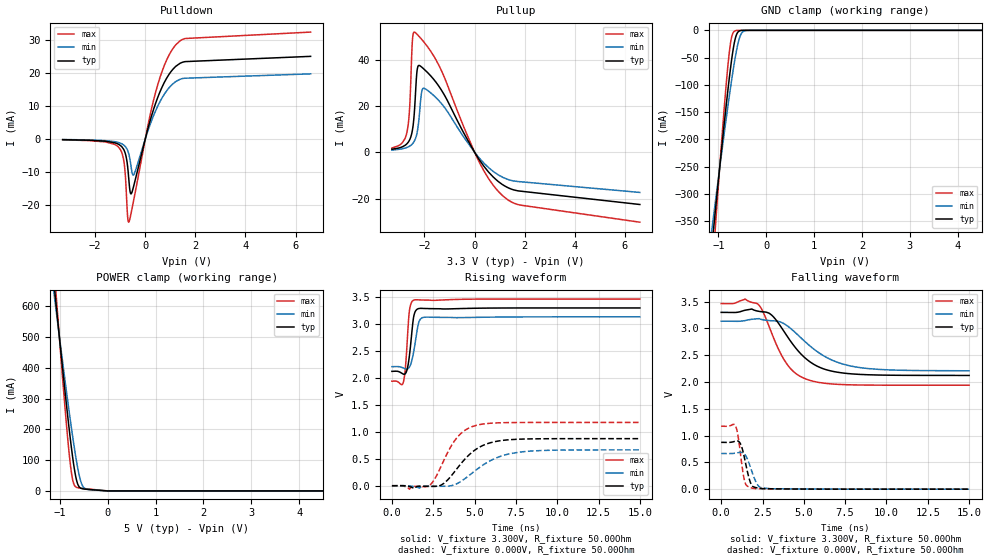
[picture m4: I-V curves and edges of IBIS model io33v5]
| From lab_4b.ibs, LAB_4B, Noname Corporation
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[Model]   io33v5
Model_type   I/O
Vinl = 800.000mV
Vinh = 2.000V
Vmeas = 1.400V
Vref = 1.400V
Cref = 5.000pF
Rref = 100.000Ohm
|   typ   min   max
C_comp   4.550pF   2.600pF   6.500pF
[Voltage Range]   3.300V   3.135V   3.465V
[Power Clamp Reference]   5.000V   4.750V   5.250V
[Temperature Range]   50.0   100.0   0.0
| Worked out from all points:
|   slope of the pulldown table from 0 to 0.495 V, typ, clamps not added: 39.6 ohm
|   slope of the pullup table from 0 to 0.495 V, typ, clamps not added: 64.4 ohm
|   GND clamp passes 1 mA (typ) near -0.56 V on its own axis
|   falling waveform, V_fixture 3.300V, R_fixture 50.00Ohm: 20-80 % time 1.92ns typ, 2.43ns min, 1.47ns max; typ from 3.3 V to 2.12 V
|   rising waveform, V_fixture 3.300V, R_fixture 50.00Ohm: 20-80 % time 247ps typ, 305ps min, 198ps max; typ from 2.12 V to 3.3 V
|   rising waveform, V_fixture 0.000V, R_fixture 50.00Ohm: 20-80 % time 1.64ns typ, 2.03ns min, 1.3ns max; typ from 0 V to 0.874 V
|   falling waveform, V_fixture 0.000V, R_fixture 50.00Ohm: 20-80 % time 392ps typ, 479ps min, 315ps max; typ from 0.874 V to 0 V
[Pulldown]
|   Voltage   I(typ)   I(min)   I(max)
-3.3V     -256.4uA   -208.9uA   -311.8uA
-1.04V    -1.786mA   -1.195mA   -2.784mA
-840mV    -3.589mA   -2.018mA   -7.696mA
-785mV    -4.824mA   -2.467mA   -12.52mA
-710mV    -8.173mA   -3.47mA    -23.22mA
-665mV    -11.73mA   -4.471mA   -25.24mA
-590mV    -16.53mA   -7.344mA   -23.33mA
-465mV    -14.31mA   -10.91mA   -18.6mA
415mV     10.84mA    8.569mA    14.2mA
845mV     18.27mA    14.46mA    23.76mA
1.22V     21.96mA    17.35mA    28.49mA
6.6V      24.96mA    19.66mA    32.31mA
[GND Clamp]
|   Voltage   I(typ)   I(min)   I(max)
-5V       -4.027A    -3.185A    -5.543A
-1.13V    -390.7mA   -361.3mA   -444.8mA
-1.1V     -363.9mA   -340.4mA   -407.5mA
-1.06V    -328.4mA   -312.7mA   -358mA
-885mV    -177.6mA   -194mA     -151.1mA
-785mV    -97.87mA   -129.4mA   -51.4mA
-720mV    -52.41mA   -89.83mA   -11.62mA
-640mV    -13.05mA   -46.25mA   -567uA
-575mV    -1.922mA   -19.09mA   -34.88uA
-520mV    -281.7uA   -5.974mA   -3.374uA
-345mV    -531nA     -33.09uA   -2.101nA
10V       27.06pA    -42.51pA   28.04pA
[Pullup]
|   Voltage   I(typ)   I(min)   I(max)
-3.3V     1.282mA    933.5uA    1.818mA
-2.685V   3.844mA    2.141mA    9.419mA
-2.59V    5.414mA    2.655mA    19.71mA
-2.48V    9.637mA    3.641mA    48.49mA
-2.4V     17.89mA    4.914mA    51.84mA
-2.285V   36.03mA    9.025mA    50.77mA
-2.13V    36.91mA    24.78mA    48.95mA
-2.03V    35.97mA    27.68mA    47.67mA
-1.345V   27.18mA    21.29mA    35.73mA
190mV     -3.263mA   -2.542mA   -4.343mA
1.17V     -14.33mA   -11.03mA   -19.21mA
6.6V      -22.55mA   -17.35mA   -30.18mA
[POWER Clamp]
|   Voltage   I(typ)   I(min)   I(max)
-5V       7.049A     5.735A     9.242A
-1.115V   662.6mA    633mA      714.6mA
-1.085V   615.9mA    595.5mA    652.6mA
-1.06V    577.2mA    564.4mA    601.3mA
-890mV    320.8mA    357mA      266.3mA
-785mV    174.6mA    234.9mA    92.52mA
-715mV    90.33mA    158.6mA    25.97mA
-630mV    23.83mA    77.41mA    10.56mA
-555mV    8.327mA    27.49mA    8.798mA
-490mV    6.13mA     9.246mA    7.697mA
0V        0A         0A         0A
10V       0A         0A         0A
[Ramp]
R_load = 50.00Ohm
|   typ   min   max
dV/dt_r   524.320mV/1.639ns   399.433mV/2.024ns   704.857mV/1.295ns
dV/dt_f   706.191mV/1.919ns   555.207mV/2.425ns   914.908mV/1.471ns
[Falling Waveform]
V_fixture = 3.300V
V_fixture_min = 3.135V
V_fixture_max = 3.465V
R_fixture = 50.00Ohm
|   Time   V(typ)   V(min)   V(max)
0s        3.3V       3.135V     3.465V
1.45ns    3.34V      3.148V     3.549V
2.225ns   3.323V     3.181V     3.453V
2.975ns   3.269V     3.145V     2.977V
3.9ns     2.898V     3.07V      2.371V
4.5ns     2.639V     2.919V     2.163V
5.275ns   2.399V     2.699V     2.04V
6.525ns   2.215V     2.435V     1.968V
8.1ns     2.148V     2.283V     1.946V
15ns      2.123V     2.21V      1.94V
[Rising Waveform]
V_fixture = 3.300V
V_fixture_min = 3.135V
V_fixture_max = 3.465V
R_fixture = 50.00Ohm
|   Time   V(typ)   V(min)   V(max)
0s        2.123V     2.21V      1.94V
700ps     2.071V     2.184V     1.931V
825ps     2.086V     2.169V     2.225V
950ps     2.198V     2.169V     2.808V
1.05ns    2.394V     2.198V     3.227V
1.15ns    2.675V     2.268V     3.379V
1.325ns   3.151V     2.502V     3.446V
1.625ns   3.289V     3.033V     3.45V
1.925ns   3.291V     3.126V     3.447V
15ns      3.3V       3.135V     3.465V
[Rising Waveform]
V_fixture = 0.000V
V_fixture_min = 0.000V
V_fixture_max = 0.000V
R_fixture = 50.00Ohm
|   Time   V(typ)   V(min)   V(max)
0s        210.3nV    222.8nV    217.9nV
1.05ns    -15.36mV   -3.806mV   -63.71mV
2.275ns   -12.4mV    -6.124mV   6.545mV
3.025ns   20.3mV     -9.96mV    394.3mV
3.875ns   293.5mV    30.42mV    868.7mV
4.425ns   497.6mV    133.5mV    1.03V
5.125ns   683.8mV    299.9mV    1.123V
6.3ns     822.7mV    514.8mV    1.166V
7.65ns    863.5mV    620.7mV    1.174V
15ns      873.9mV    665.7mV    1.175V
[Falling Waveform]
V_fixture = 0.000V
V_fixture_min = 0.000V
V_fixture_max = 0.000V
R_fixture = 50.00Ohm
|   Time   V(typ)   V(min)   V(max)
0s        873.9mV    665.7mV    1.175V
875ps     897.8mV    673mV      1.175V
1ns       899.8mV    680mV      1.028V
1.175ns   841.3mV    687.3mV    638.5mV
1.425ns   560.1mV    648.5mV    143.9mV
1.675ns   217.1mV    493.7mV    40.83mV
1.85ns    71.8mV     336.7mV    21.34mV
2.275ns   18.49mV    52.78mV    10.99mV
2.9ns     8.506mV    11.35mV    5.477mV
15ns      210.3nV    222.8nV    217.9nV
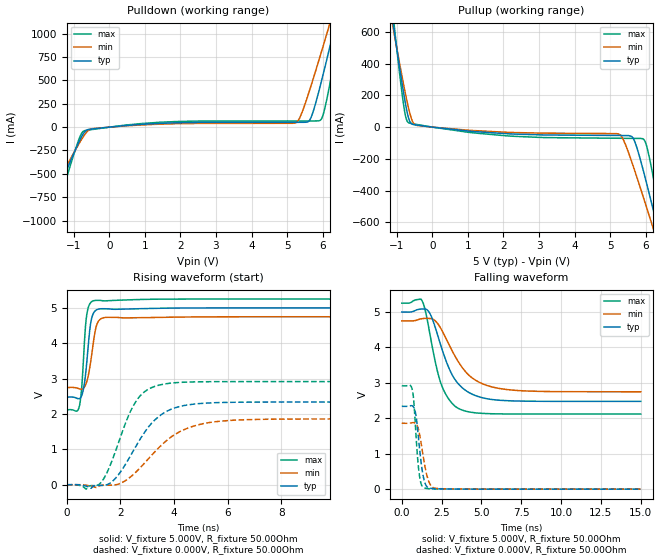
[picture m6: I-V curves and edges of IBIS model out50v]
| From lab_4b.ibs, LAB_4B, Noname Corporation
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[Model]   out50v
Model_type   Output
Vmeas = 1.400V
Vref = 1.400V
Cref = 5.000pF
Rref = 100.000Ohm
|   typ   min   max
C_comp   4.550pF   2.600pF   6.500pF
[Voltage Range]   5.000V   4.750V   5.250V
[Temperature Range]   50.0   100.0   0.0
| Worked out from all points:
|   slope of the pulldown table from 0 to 0.75 V, typ, clamps not added: 29.6 ohm
|   slope of the pullup table from 0 to 0.75 V, typ, clamps not added: 40.8 ohm
|   falling waveform, V_fixture 5.000V, R_fixture 50.00Ohm: 20-80 % time 1.38ns typ, 1.72ns min, 1.02ns max; typ from 5 V to 2.48 V
|   rising waveform, V_fixture 5.000V, R_fixture 50.00Ohm: 20-80 % time 198ps typ, 242ps min, 160ps max; typ from 2.48 V to 5 V
|   rising waveform, V_fixture 0.000V, R_fixture 50.00Ohm: 20-80 % time 1.25ns typ, 1.59ns min, 926ps max; typ from 0 V to 2.34 V
|   falling waveform, V_fixture 0.000V, R_fixture 50.00Ohm: 20-80 % time 355ps typ, 444ps min, 276ps max; typ from 2.34 V to 0 V
[Pulldown]
|   Voltage   I(typ)   I(min)   I(max)
-5V       -4.027A    -3.186A    -5.543A
-2.02V    -1.212A    -998.9mA   -1.596A
-1.595V   -816.4mA   -692.1mA   -1.041A
-870mV    -169.3mA   -186.6mA   -143.1mA
-605mV    -26.32mA   -39.23mA   -31.47mA
5.255V    51.67mA    48.79mA    66.3mA
5.675V    102.2mA    442.2mA    66.49mA
5.985V    517.2mA    828.1mA    99.84mA
6.205V    859.5mA    1.109A     460.6mA
6.325V    1.05A      1.264A     703.1mA
6.525V    1.372A     1.523A     1.123A
10V       7.106A     6.113A     8.761A
[Pullup]
|   Voltage   I(typ)   I(min)   I(max)
-5V       7.053A     5.738A     9.247A
-1.14V    706.4mA    668mA      773.1mA
-1.04V    551.2mA    543.3mA    567.1mA
-780mV    174mA      233.3mA    96.12mA
-665mV    52.44mA    113.3mA    27.17mA
-435mV    12.72mA    10.87mA    16.65mA
5.225V    -52.62mA   -42.21mA   -70.19mA
5.635V    -64.76mA   -235mA     -70.95mA
5.915V    -256.3mA   -427mA     -73.05mA
6.21V     -516.7mA   -636.2mA   -309.2mA
6.53V     -809.9mA   -866.6mA   -706.9mA
10V       -4.086A    -3.416A    -5.289A
[Ramp]
R_load = 50.00Ohm
|   typ   min   max
dV/dt_r   1.403V/1.244ns   1.116V/1.586ns   1.750V/924.101ps
dV/dt_f   1.513V/1.382ns   1.201V/1.723ns   1.878V/1.016ns
[Falling Waveform]
V_fixture = 5.000V
V_fixture_min = 4.750V
V_fixture_max = 5.250V
R_fixture = 50.00Ohm
|   Time   V(typ)   V(min)   V(max)
0s        5V         4.75V      5.25V
1.275ns   5.086V     4.812V     5.317V
1.5ns     5.086V     4.82V      4.998V
1.775ns   4.951V     4.817V     4.359V
2.45ns    4.059V     4.538V     2.998V
3.075ns   3.305V     3.982V     2.467V
3.65ns    2.925V     3.527V     2.259V
4.65ns    2.637V     3.07V      2.154V
6.225ns   2.507V     2.835V     2.124V
15ns      2.478V     2.748V     2.121V
[Rising Waveform]
V_fixture = 5.000V
V_fixture_min = 4.750V
V_fixture_max = 5.250V
R_fixture = 50.00Ohm
|   Time   V(typ)   V(min)   V(max)
0s        2.478V     2.748V     2.121V
475ps     2.437V     2.711V     2.239V
550ps     2.51V      2.703V     2.683V
650ps     2.826V     2.755V     3.919V
725ps     3.3V       2.872V     4.693V
875ps     4.487V     3.396V     5.135V
1ns       4.857V     4.066V     5.203V
1.175ns   4.965V     4.617V     5.214V
1.5ns     4.974V     4.733V     5.202V
15ns      5V         4.75V      5.25V
[Rising Waveform]
V_fixture = 0.000V
V_fixture_min = 0.000V
V_fixture_max = 0.000V
R_fixture = 50.00Ohm
|   Time   V(typ)   V(min)   V(max)
0s        27.12nV    271.5nV    5.17nV
725ps     -40.2mV    -14.6mV    -125.2mV
1.275ns   -18.53mV   -18.42mV   62.91mV
1.825ns   190.8mV    -905.1uV   966mV
2.525ns   1.018V     320.3mV    2.29V
2.9ns     1.481V     613.8mV    2.63V
3.425ns   1.925V     1.042V     2.814V
4.35ns    2.235V     1.55V      2.898V
5.675ns   2.323V     1.793V     2.915V
15ns      2.339V     1.861V     2.916V
[Falling Waveform]
V_fixture = 0.000V
V_fixture_min = 0.000V
V_fixture_max = 0.000V
R_fixture = 50.00Ohm
|   Time   V(typ)   V(min)   V(max)
0s        2.339V     1.861V     2.916V
650ps     2.353V     1.875V     2.828V
750ps     2.311V     1.878V     2.507V
875ps     2.123V     1.854V     1.661V
1.075ns   1.328V     1.643V     507.4mV
1.225ns   717.3mV    1.267V     137mV
1.425ns   219.2mV    717.8mV    36.63mV
1.75ns    32.62mV    160.5mV    12.68mV
2.2ns     11.18mV    21.94mV    6.639mV
15ns      27.12nV    271.5nV    5.17nV
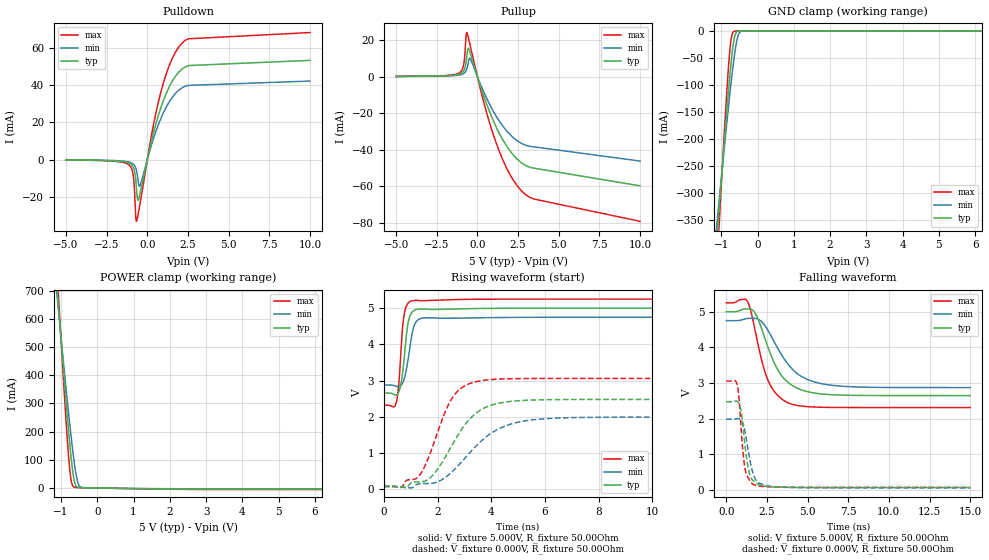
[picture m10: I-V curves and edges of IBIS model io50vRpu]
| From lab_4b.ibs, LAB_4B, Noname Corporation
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[Model]   io50vRpu
Model_type   I/O
Vinl = 800.000mV
Vinh = 2.000V
Vmeas = 1.400V
Vref = 1.400V
Cref = 5.000pF
Rref = 100.000Ohm
|   typ   min   max
C_comp   4.550pF   2.600pF   6.500pF
[Voltage Range]   5.000V   4.750V   5.250V
[Temperature Range]   50.0   100.0   0.0
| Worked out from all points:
|   slope of the pulldown table from 0 to 0.75 V, typ, clamps not added: 29.2 ohm
|   slope of the pullup table from 0 to 0.75 V, typ, clamps not added: 39 ohm
|   GND clamp passes 1 mA (typ) near -0.55 V on its own axis
|   POWER clamp passes 1 mA (typ) near -0.40 V on its own axis
|   falling waveform, V_fixture 5.000V, R_fixture 50.00Ohm: 20-80 % time 1.4ns typ, 1.73ns min, 1.07ns max; typ from 5 V to 2.65 V
|   rising waveform, V_fixture 5.000V, R_fixture 50.00Ohm: 20-80 % time 207ps typ, 250ps min, 169ps max; typ from 2.65 V to 5 V
|   rising waveform, V_fixture 0.000V, R_fixture 50.00Ohm: 20-80 % time 1.28ns typ, 1.63ns min, 951ps max; typ from 0.071 V to 2.48 V
|   falling waveform, V_fixture 0.000V, R_fixture 50.00Ohm: 20-80 % time 403ps typ, 492ps min, 326ps max; typ from 2.48 V to 0.071 V
[Pulldown]
|   Voltage   I(typ)   I(min)   I(max)
-5V       -207.1uA   -171.2uA   -248.8uA
-1.13V    -1.927mA   -1.335mA   -2.852mA
-860mV    -4.389mA   -2.516mA   -9.028mA
-710mV    -11.07mA   -4.645mA   -31mA
-670mV    -15.23mA   -5.818mA   -33.25mA
-575mV    -21.91mA   -10.83mA   -29.94mA
-445mV    -18.01mA   -13.98mA   -23.51mA
265mV     10.33mA    8.149mA    13.57mA
790mV     26.82mA    21.25mA    34.93mA
1.37V     39.56mA    31.41mA    51.13mA
2.085V    48.39mA    38.37mA    62.25mA
10V       53.44mA    42.3mA     68.42mA
[GND Clamp]
|   Voltage   I(typ)   I(min)   I(max)
-5V       -4.027A    -3.186A    -5.543A
-1.13V    -390.8mA   -361.4mA   -445mA
-1.1V     -364mA     -340.5mA   -407.6mA
-1.06V    -328.5mA   -312.8mA   -358.2mA
-885mV    -177.7mA   -194.1mA   -151.3mA
-785mV    -97.96mA   -129.5mA   -51.52mA
-720mV    -52.49mA   -89.9mA    -11.73mA
-640mV    -13.13mA   -46.31mA   -666uA
-575mV    -1.992mA   -19.15mA   -123.8uA
-520mV    -345.2uA   -6.025mA   -83.8uA
-345mV    -42.67uA   -67.14uA   -53.34uA
10V       0A         0A         0A
[Pullup]
|   Voltage   I(typ)   I(min)   I(max)
-5V       149.8uA    122.3uA    183uA
-1.115V   1.394mA    953.8uA    2.1mA
-845mV    3.186mA    1.803mA    6.687mA
-660mV    10.77mA    4.081mA    24.18mA
-570mV    15.65mA    7.386mA    21.72mA
-440mV    12.84mA    9.88mA     16.84mA
340mV     -9.372mA   -7.373mA   -12.34mA
1.035V    -25.27mA   -19.83mA   -33.28mA
1.84V     -38.53mA   -30.1mA    -50.84mA
2.665V    -46.8mA    -36.26mA   -62.03mA
3.52V     -50.13mA   -38.44mA   -67.04mA
10V       -59.71mA   -46.16mA   -79.14mA
[POWER Clamp]
|   Voltage   I(typ)   I(min)   I(max)
-5V       7.64A      6.217A     10.02A
-1.11V    713.1mA    682mA      767.9mA
-1.08V    662.5mA    641.3mA    700.7mA
-1.055V   620.5mA    607.6mA    645mA
-885mV    342.6mA    382.8mA    281.8mA
-780mV    184mA      250.5mA    92.53mA
-715mV    98.29mA    173.5mA    22.03mA
-635mV    24.95mA    88.98mA    2.939mA
-570mV    4.772mA    36.76mA    1.871mA
-515mV    1.75mA     11.97mA    1.645mA
-340mV    828.8uA    714.4uA    1.086mA
10V       -4.357mA   -3.324mA   -5.853mA
[Ramp]
R_load = 50.00Ohm
|   typ   min   max
dV/dt_r   1.444V/1.276ns   1.155V/1.632ns   1.787V/950.785ps
dV/dt_f   1.410V/1.395ns   1.126V/1.725ns   1.761V/1.073ns
[Falling Waveform]
V_fixture = 5.000V
V_fixture_min = 4.750V
V_fixture_max = 5.250V
R_fixture = 50.00Ohm
|   Time   V(typ)   V(min)   V(max)
0s        5V         4.75V      5.25V
1.275ns   5.08V      4.809V     5.306V
1.5ns     5.078V     4.816V     5.033V
1.8ns     4.939V     4.812V     4.418V
2.525ns   4.058V     4.506V     3.124V
3.125ns   3.408V     4.007V     2.673V
3.825ns   3.009V     3.514V     2.442V
4.85ns    2.777V     3.13V      2.345V
6.525ns   2.673V     2.936V     2.318V
15ns      2.649V     2.873V     2.315V
[Rising Waveform]
V_fixture = 5.000V
V_fixture_min = 4.750V
V_fixture_max = 5.250V
R_fixture = 50.00Ohm
|   Time   V(typ)   V(min)   V(max)
0s        2.649V     2.873V     2.315V
450ps     2.599V     2.845V     2.363V
550ps     2.677V     2.831V     2.878V
625ps     2.874V     2.857V     3.696V
750ps     3.592V     3.037V     4.813V
875ps     4.483V     3.467V     5.114V
1.025ns   4.866V     4.197V     5.201V
1.2ns     4.962V     4.624V     5.215V
1.55ns    4.975V     4.733V     5.209V
15ns      5V         4.75V      5.25V
[Rising Waveform]
V_fixture = 0.000V
V_fixture_min = 0.000V
V_fixture_max = 0.000V
R_fixture = 50.00Ohm
|   Time   V(typ)   V(min)   V(max)
0s        71.38mV    63.44mV    79.04mV
675ps     49.15mV    54.35mV    49.92mV
1.3ns     196.8mV    144.5mV    354.6mV
1.8ns     366.5mV    158.4mV    1.144V
2.5ns     1.162V     450.1mV    2.461V
2.85ns    1.598V     714.3mV    2.772V
3.35ns    2.045V     1.123V     2.952V
4.325ns   2.378V     1.679V     3.041V
5.6ns     2.462V     1.919V     3.056V
15ns      2.477V     1.988V     3.057V
[Falling Waveform]
V_fixture = 0.000V
V_fixture_min = 0.000V
V_fixture_max = 0.000V
R_fixture = 50.00Ohm
|   Time   V(typ)   V(min)   V(max)
0s        2.477V     1.988V     3.057V
675ps     2.487V     2.002V     2.948V
775ps     2.44V      2.003V     2.616V
900ps     2.245V     1.975V     1.816V
1.025ns   1.795V     1.877V     1.076V
1.15ns    1.265V     1.652V     615mV
1.4ns     511.3mV    980.1mV    303.8mV
1.725ns   240.2mV    368.8mV    148.9mV
3.25ns    83.54mV    86.29mV    83.46mV
15ns      71.38mV    63.44mV    79.04mV
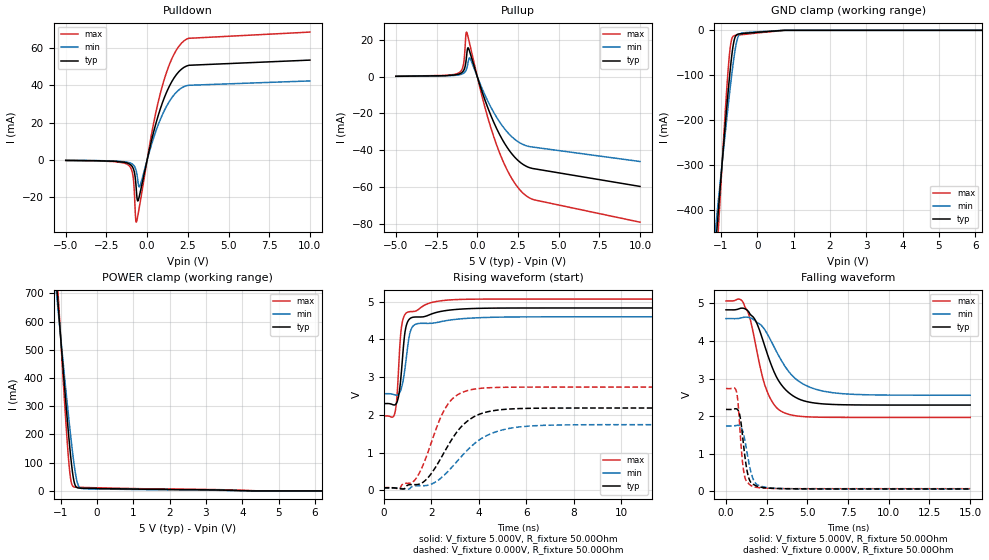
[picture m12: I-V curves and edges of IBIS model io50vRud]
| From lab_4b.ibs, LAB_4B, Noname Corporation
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[Model]   io50vRud
Model_type   I/O
Vinl = 800.000mV
Vinh = 2.000V
Vmeas = 1.400V
Vref = 1.400V
Cref = 5.000pF
Rref = 100.000Ohm
|   typ   min   max
C_comp   4.550pF   2.600pF   6.500pF
[Voltage Range]   5.000V   4.750V   5.250V
[Temperature Range]   50.0   100.0   0.0
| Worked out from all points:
|   slope of the pulldown table from 0 to 0.75 V, typ, clamps not added: 29.2 ohm
|   slope of the pullup table from 0 to 0.75 V, typ, clamps not added: 39 ohm
|   falling waveform, V_fixture 5.000V, R_fixture 50.00Ohm: 20-80 % time 1.43ns typ, 1.83ns min, 1.04ns max; typ from 4.83 V to 2.3 V
|   rising waveform, V_fixture 5.000V, R_fixture 50.00Ohm: 20-80 % time 241ps typ, 281ps min, 211ps max; typ from 2.3 V to 4.83 V
|   rising waveform, V_fixture 0.000V, R_fixture 50.00Ohm: 20-80 % time 1.33ns typ, 1.66ns min, 1.01ns max; typ from 0.064 V to 2.18 V
|   falling waveform, V_fixture 0.000V, R_fixture 50.00Ohm: 20-80 % time 379ps typ, 473ps min, 296ps max; typ from 2.18 V to 0.064 V
[Pulldown]
|   Voltage   I(typ)   I(min)   I(max)
-5V       -207.1uA   -171.2uA   -248.8uA
-1.13V    -1.927mA   -1.335mA   -2.852mA
-860mV    -4.389mA   -2.516mA   -9.028mA
-710mV    -11.07mA   -4.645mA   -31mA
-670mV    -15.23mA   -5.818mA   -33.25mA
-575mV    -21.91mA   -10.83mA   -29.94mA
-445mV    -18.01mA   -13.98mA   -23.51mA
265mV     10.33mA    8.149mA    13.57mA
790mV     26.82mA    21.25mA    34.93mA
1.37V     39.56mA    31.41mA    51.13mA
2.085V    48.39mA    38.37mA    62.25mA
10V       53.44mA    42.3mA     68.42mA
[GND Clamp]
|   Voltage   I(typ)   I(min)   I(max)
-5V       -4.703A    -3.72A     -6.473A
-1.24V    -576.2mA   -515.1mA   -687.1mA
-1.135V   -465.8mA   -429.2mA   -532.8mA
-1.085V   -413.8mA   -388.7mA   -460.2mA
-1.06V    -388mA     -368.5mA   -424.3mA
-880mV    -207.4mA   -226.3mA   -177.2mA
-765mV    -102.6mA   -140.4mA   -51.39mA
-715mV    -63.7mA    -105.5mA   -22.6mA
-655mV    -28.65mA   -67.2mA    -12.71mA
-545mV    -8.801mA   -17.96mA   -10.7mA
715mV     -141.5uA   0A         -359uA
10V       0A         0A         0A
[Pullup]
|   Voltage   I(typ)   I(min)   I(max)
-5V       149.8uA    122.3uA    183uA
-1.115V   1.394mA    953.8uA    2.1mA
-845mV    3.186mA    1.803mA    6.687mA
-660mV    10.77mA    4.081mA    24.18mA
-570mV    15.65mA    7.386mA    21.72mA
-440mV    12.84mA    9.88mA     16.84mA
340mV     -9.372mA   -7.373mA   -12.34mA
1.035V    -25.27mA   -19.83mA   -33.28mA
1.84V     -38.53mA   -30.1mA    -50.84mA
2.665V    -46.8mA    -36.26mA   -62.03mA
3.52V     -50.13mA   -38.44mA   -67.04mA
10V       -59.71mA   -46.16mA   -79.14mA
[POWER Clamp]
|   Voltage   I(typ)   I(min)   I(max)
-5V       7.649A     6.224A     10.03A
-1.11V    721.8mA    688.8mA    779mA
-1.08V    671.2mA    648.2mA    711.8mA
-1.03V    587.4mA    580.9mA    600.9mA
-850mV    296.7mA    344.8mA    224.4mA
-780mV    192.6mA    257.3mA    103.6mA
-715mV    106.9mA    180.3mA    33.13mA
-635mV    33.58mA    95.79mA    14.04mA
-570mV    13.4mA     43.57mA    12.96mA
-515mV    10.38mA    18.78mA    12.73mA
-340mV    9.446mA    7.508mA    12.16mA
10V       0A         0A         0A
[Ramp]
R_load = 50.00Ohm
|   typ   min   max
dV/dt_r   1.269V/1.328ns   1.009V/1.661ns   1.598V/1.009ns
dV/dt_f   1.521V/1.431ns   1.224V/1.826ns   1.860V/1.036ns
[Falling Waveform]
V_fixture = 5.000V
V_fixture_min = 4.750V
V_fixture_max = 5.250V
R_fixture = 50.00Ohm
|   Time   V(typ)   V(min)   V(max)
0s        4.831V     4.597V     5.067V
1.075ns   4.872V     4.63V      5.01V
1.475ns   4.719V     4.619V     4.599V
1.825ns   4.536V     4.521V     3.888V
2.45ns    3.775V     4.253V     2.747V
2.975ns   3.159V     3.826V     2.294V
3.525ns   2.769V     3.395V     2.101V
4.575ns   2.439V     2.899V     1.996V
6.025ns   2.325V     2.662V     1.971V
15ns      2.296V     2.557V     1.967V
[Rising Waveform]
V_fixture = 5.000V
V_fixture_min = 4.750V
V_fixture_max = 5.250V
R_fixture = 50.00Ohm
|   Time   V(typ)   V(min)   V(max)
0s        2.296V     2.557V     1.967V
475ps     2.263V     2.526V     2.056V
575ps     2.357V     2.521V     2.612V
675ps     2.685V     2.586V     3.77V
750ps     3.163V     2.712V     4.322V
850ps     3.931V     3.019V     4.601V
975ps     4.412V     3.622V     4.709V
1.175ns   4.575V     4.29V      4.736V
1.925ns   4.65V      4.423V     4.959V
15ns      4.831V     4.597V     5.067V
[Rising Waveform]
V_fixture = 0.000V
V_fixture_min = 0.000V
V_fixture_max = 0.000V
R_fixture = 50.00Ohm
|   Time   V(typ)   V(min)   V(max)
0s        64.12mV    57.48mV    70.36mV
675ps     43.59mV    49.12mV    40.92mV
1.325ns   148.5mV    119mV      279.5mV
1.875ns   339.8mV    135.5mV    1.029V
2.6ns     1.063V     430.8mV    2.178V
2.975ns   1.451V     684.4mV    2.47V
3.525ns   1.833V     1.065V     2.642V
4.4ns     2.083V     1.468V     2.716V
5.725ns   2.165V     1.679V     2.732V
15ns      2.18V      1.739V     2.734V
[Falling Waveform]
V_fixture = 0.000V
V_fixture_min = 0.000V
V_fixture_max = 0.000V
R_fixture = 50.00Ohm
|   Time   V(typ)   V(min)   V(max)
0s        2.18V      1.739V     2.734V
650ps     2.194V     1.753V     2.639V
750ps     2.152V     1.756V     2.308V
875ps     1.965V     1.733V     1.535V
1.1ns     1.154V     1.49V      501.4mV
1.35ns    434.9mV    893.3mV    225.6mV
1.625ns   197.4mV    378.7mV    134.1mV
1.95ns    130.2mV    166.7mV    101.3mV
3.15ns    75.25mV    78.03mV    74.51mV
15ns      64.12mV    57.48mV    70.36mV
